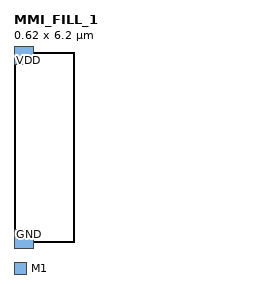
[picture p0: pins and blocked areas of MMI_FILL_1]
MACRO MMI_FILL_1
	CLASS CORE ;
	FOREIGN MMI_FILL_1 0 0 ;
	SIZE 0.62 BY 6.2 ;
	SYMMETRY X Y ;
	SITE CORE1 ;
	PIN GND
		DIRECTION inout ;
		USE GROUND ;
		PORT
			LAYER M1 ;
			RECT 0 -0.42 0.62 0.42 ;
		END
	END GND
	PIN VDD
		DIRECTION inout ;
		USE POWER ;
		PORT
			LAYER M1 ;
			RECT 0 5.78 0.62 6.62 ;
		END
	END VDD
	OBS
	END
END MMI_FILL_1
